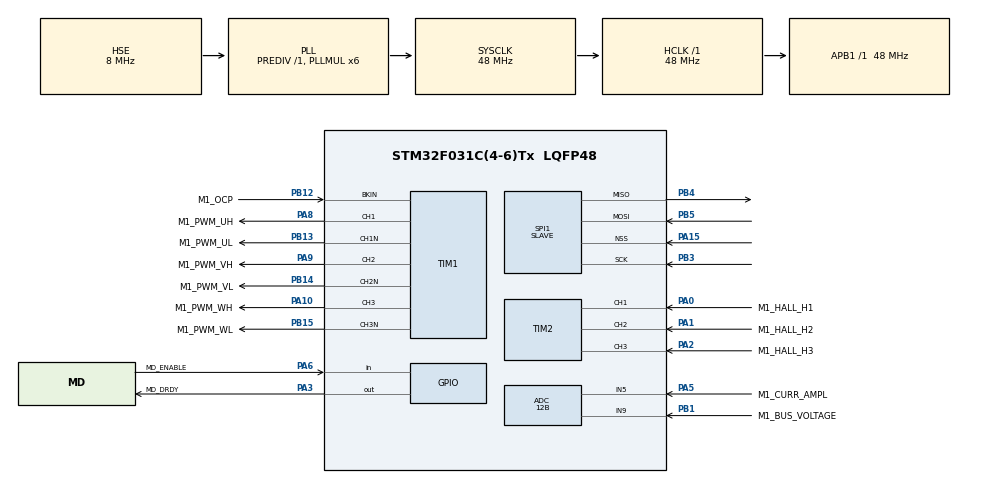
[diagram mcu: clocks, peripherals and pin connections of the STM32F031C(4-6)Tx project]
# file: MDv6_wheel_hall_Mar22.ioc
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ADC.ClockPrescaler=ADC_CLOCK_ASYNC_DIV1
ADC.ContinuousConvMode=DISABLE
ADC.DMAContinuousRequests=ENABLE
ADC.DataAlign=ADC_DATAALIGN_LEFT
ADC.DiscontinuousConvMode=DISABLE
ADC.EOCSelection=ADC_EOC_SINGLE_CONV
ADC.EnableAnalogWatchDog=false
ADC.ExternalTrigConv=ADC_EXTERNALTRIGCONV_T1_TRGO
ADC.ExternalTrigConvEdge=ADC_EXTERNALTRIGCONVEDGE_RISING
ADC.LowPowerAutoPowerOff=DISABLE
ADC.LowPowerAutoWait=DISABLE
ADC.Overrun=ADC_OVR_DATA_PRESERVED
ADC.Resolution=ADC_RESOLUTION_12B
ADC.SamplingTime=ADC_SAMPLETIME_7CYCLES_5
ADC.ScanConvMode=ADC_SCAN_DIRECTION_FORWARD
Dma.ADC.0.Direction=DMA_PERIPH_TO_MEMORY
Dma.ADC.0.Instance=DMA1_Channel1
Dma.ADC.0.MemDataAlignment=DMA_MDATAALIGN_HALFWORD
Dma.ADC.0.MemInc=DMA_MINC_ENABLE
Dma.ADC.0.Mode=DMA_CIRCULAR
Dma.ADC.0.PeriphDataAlignment=DMA_PDATAALIGN_HALFWORD
Dma.ADC.0.PeriphInc=DMA_PINC_DISABLE
Dma.ADC.0.Priority=DMA_PRIORITY_LOW
Dma.Request0=ADC
Dma.Request1=TIM1_CH4/TRIG/COM
Dma.Request2=TIM1_CH3/UP
Dma.Request3=SPI1_RX
Dma.Request4=SPI1_TX
Dma.SPI1_RX.3.Direction=DMA_PERIPH_TO_MEMORY
Dma.SPI1_RX.3.Instance=DMA1_Channel2
Dma.SPI1_RX.3.MemDataAlignment=DMA_MDATAALIGN_BYTE
Dma.SPI1_RX.3.MemInc=DMA_MINC_ENABLE
Dma.SPI1_RX.3.Mode=DMA_CIRCULAR
Dma.SPI1_RX.3.PeriphDataAlignment=DMA_PDATAALIGN_BYTE
Dma.SPI1_RX.3.PeriphInc=DMA_PINC_DISABLE
Dma.SPI1_RX.3.Priority=DMA_PRIORITY_LOW
Dma.SPI1_TX.4.Direction=DMA_MEMORY_TO_PERIPH
Dma.SPI1_TX.4.Instance=DMA1_Channel3
Dma.SPI1_TX.4.MemDataAlignment=DMA_MDATAALIGN_BYTE
Dma.SPI1_TX.4.MemInc=DMA_MINC_ENABLE
Dma.SPI1_TX.4.Mode=DMA_CIRCULAR
Dma.SPI1_TX.4.PeriphDataAlignment=DMA_PDATAALIGN_BYTE
Dma.SPI1_TX.4.PeriphInc=DMA_PINC_DISABLE
Dma.SPI1_TX.4.Priority=DMA_PRIORITY_LOW
Dma.TIM1_CH3/UP.2.Direction=DMA_MEMORY_TO_PERIPH
Dma.TIM1_CH3/UP.2.Instance=DMA1_Channel5
Dma.TIM1_CH3/UP.2.MemDataAlignment=DMA_MDATAALIGN_HALFWORD
Dma.TIM1_CH3/UP.2.MemInc=DMA_MINC_ENABLE
Dma.TIM1_CH3/UP.2.Mode=DMA_CIRCULAR
Dma.TIM1_CH3/UP.2.PeriphDataAlignment=DMA_PDATAALIGN_HALFWORD
Dma.TIM1_CH3/UP.2.PeriphInc=DMA_PINC_DISABLE
Dma.TIM1_CH3/UP.2.Priority=DMA_PRIORITY_HIGH
Dma.TIM1_CH4/TRIG/COM.1.Direction=DMA_MEMORY_TO_PERIPH
Dma.TIM1_CH4/TRIG/COM.1.Instance=DMA1_Channel4
Dma.TIM1_CH4/TRIG/COM.1.MemDataAlignment=DMA_MDATAALIGN_HALFWORD
Dma.TIM1_CH4/TRIG/COM.1.MemInc=DMA_MINC_ENABLE
Dma.TIM1_CH4/TRIG/COM.1.Mode=DMA_CIRCULAR
Dma.TIM1_CH4/TRIG/COM.1.PeriphDataAlignment=DMA_PDATAALIGN_HALFWORD
Dma.TIM1_CH4/TRIG/COM.1.PeriphInc=DMA_PINC_DISABLE
Dma.TIM1_CH4/TRIG/COM.1.Priority=DMA_PRIORITY_HIGH
ExtraMW=MotorControl
ExtraMW.MotorControl.Config=MotorControl
ExtraMW.MotorControl.Mode=MotorControl
ExtraMW.MotorControl.Root=MCSDK_v6.4.1-Full/MotorControl
ExtraMW.MotorControl.Template=templates
Mcu.Family=STM32F0
Mcu.Name=STM32F031C(4-6)Tx
Mcu.Package=LQFP48
MotorControl.ADC_AHBPERIPH=RCC_AHBPeriph_ADC
MotorControl.ADC_CLOCK_WB_DIV=1
MotorControl.ADC_PERIPH=ADC1
MotorControl.ADC_REFERENCE_VOLTAGE=3.3
MotorControl.BOARD=EVSPIN32F0251S1
MotorControl.BUS_VOLTAGE_READING=true
MotorControl.CCMRAM_ENABLED=false
MotorControl.CLOCK_FREQUENCY=CPU_CLK_48_MHZ
MotorControl.CLOCK_SOURCE=EXTERNAL
MotorControl.CONFIG_OC_SEL=false
MotorControl.CPU_CLK_48_MHZ=true
MotorControl.CTLBOARD_NAME=EVSPIN32F0251S1
MotorControl.CUBE_MX_VER=6.9.2
MotorControl.CURRENT_READING_TOPOLOGY=SINGLE_SHUNT
MotorControl.CURR_SAMPLING_TIME=7
MotorControl.DBG_MCU_LOAD_MEASURE=false
MotorControl.DEBUG_DAC_FUNCTIONALITY_EN=false
MotorControl.DRIVES_NUMBER_SELECTION=SINGLEDRIVE
MotorControl.DRIVE_NUMBER=1
MotorControl.DRIVE_TYPE=FOC
MotorControl.EMERGENCY_STOP_GPIO_PIN=LL_GPIO_PIN_12
MotorControl.EMERGENCY_STOP_GPIO_PORT=GPIOB
MotorControl.ENCODER_AVAILABLE=false
MotorControl.ENCODER_PPR=400
MotorControl.EN_DRIVER_AVAILABLE=true
MotorControl.EN_DRIVER_GPIO_PIN=LL_GPIO_PIN_11
MotorControl.EN_DRIVER_GPIO_PORT=GPIOA
MotorControl.EN_DRIVER_POLARITY=ACTIVE_LOW
MotorControl.EXT_CLK_8_MHZ=true
MotorControl.EXT_CLOCK_FREQUENCY=EXT_CLK_8_MHZ
MotorControl.FEEDBACK_NET_FILTERING=false
MotorControl.H1_GPIO_PIN=LL_GPIO_PIN_0
MotorControl.H1_GPIO_PORT=GPIOA
MotorControl.H2_GPIO_PIN=LL_GPIO_PIN_1
MotorControl.H2_GPIO_PORT=GPIOA
MotorControl.H3_GPIO_PIN=LL_GPIO_PIN_2
MotorControl.H3_GPIO_PORT=GPIOA
MotorControl.HALL_ICx_FILTER=34
MotorControl.HALL_SENSORS=true
MotorControl.HALL_SENSORS_AVAILABLE=true
MotorControl.HALL_TIMER_SELECTION=HALL_TIM2
MotorControl.HIGH_SIDE_IDLE_STATE=false
MotorControl.HWV_CS=SingleShunt_AmplifiedCurrents
MotorControl.HWV_OCP=SingleInput_RawCurrents_Protection_IntRef
MotorControl.HWV_PWM=PoweringHighAndLowSides
MotorControl.HW_COMPLEMENTED_LOW_SIDE=false
MotorControl.HW_DEAD_TIME_NS=700
MotorControl.IPs=NVIC,RCC,SYS,MotorControl,TIM1,ADC,TIM2,USART1,DMA
MotorControl.LOW_MEMORY_FOOTPRINT_REG=true
MotorControl.LOW_SIDE_IDLE_STATE=false
MotorControl.LOW_SIDE_SIGNALS_ENABLING=LS_PWM_TIMER
MotorControl.M1_AMPLIFICATION_GAIN=3.33
MotorControl.M1_ANGC={0,0,0,0,0,0,0,0}
MotorControl.M1_AUXILIARY_SPEED_SENSOR=NONE
MotorControl.M1_BOARD_MAX_CURRENT=9.5
MotorControl.M1_BUS_VOLTAGE_READING=true
MotorControl.M1_CONSTANT1_D=21860
MotorControl.M1_CONSTANT1_Q=21860
MotorControl.M1_CONSTANT2_QD=1876
MotorControl.M1_CS_ADC_NUM=1
MotorControl.M1_CS_ADC_PHASE_SHARED=NONE
MotorControl.M1_CS_ADC_U=ADC1
MotorControl.M1_CS_CHANNEL_U=5
MotorControl.M1_CURRENT_AMPLIFICATION_TOPO=EXTERNAL
MotorControl.M1_CURRENT_SENSING_TOPO=SINGLE_SHUNT_PHASE_SHIFT
MotorControl.M1_CURR_SAMPLING_TIME=7
MotorControl.M1_DBG_OPEN_LOOP_ENABLE=false
MotorControl.M1_DC_CURRENT_RS_MEAS=9.5
MotorControl.M1_DEFAULT_CONTROL_MODE=STC_SPEED_MODE
MotorControl.M1_DEFAULT_FLUX_COMPONENT=0
MotorControl.M1_DEFAULT_TARGET_SPEED_RPM=1742
MotorControl.M1_DEFAULT_TORQUE_COMPONENT=0
MotorControl.M1_DISCONTINUOUS_PWM=false
MotorControl.M1_DP_TOPOLOGY=NONE
MotorControl.M1_DRIVE_TYPE=FOC
MotorControl.M1_ENCODER_PPR=400
MotorControl.M1_FEED_FORWARD_CURRENT_REG_ENABLING=false
MotorControl.M1_FLUX_WEAKENING_ENABLING=false
MotorControl.M1_FW_KIDIV=32768
MotorControl.M1_FW_KI_GAIN=5000
MotorControl.M1_FW_KPDIV=32768
MotorControl.M1_FW_KP_GAIN=3000
MotorControl.M1_FW_VOLTAGE_REF=985
MotorControl.M1_HALL_AVERAGING_FIFO_DEPTH=16
MotorControl.M1_HALL_ICx_FILTER=34
MotorControl.M1_HALL_MTPA=false
MotorControl.M1_HALL_PHASE_SHIFT=270
MotorControl.M1_HALL_SENSORS_PLACEMENT=DEGREES_120
MotorControl.M1_HALL_TIMER_SELECTION=HALL_TIM2
MotorControl.M1_HIGH_SIDE_IDLE_STATE=false
MotorControl.M1_HW_DEAD_TIME_NS=700
MotorControl.M1_ICL_ENABLED=false
MotorControl.M1_ID_DEMAG=-9.5
MotorControl.M1_IQMAX=9.5
MotorControl.M1_LDLQ_RATIO=1.000
MotorControl.M1_LOW_SIDE_IDLE_STATE=false
MotorControl.M1_LOW_SIDE_SIGNALS_ENABLING=LS_PWM_TIMER
MotorControl.M1_LS=0.00027
MotorControl.M1_MAX_APPLICATION_SPEED=4840
MotorControl.M1_MAX_MODULATION_INDEX=100
MotorControl.M1_MIN_APPLICATION_SPEED=0
MotorControl.M1_MOTOR_MAX_SPEED_RPM=4840
MotorControl.M1_MOTOR_NAME=DF45L024048-A2
MotorControl.M1_MOTOR_RATED_FLUX=0.023086441
MotorControl.M1_MOTOR_VOLTAGE_CONSTANT=3.8
MotorControl.M1_MTPA_ENABLING=false
MotorControl.M1_NOMINAL_BUS_VOLTAGE_V=24
MotorControl.M1_NOMINAL_CURRENT=9.5
MotorControl.M1_OCP_BKIN_FILTER=3
MotorControl.M1_OCP_BKIN_MODE=EXT_MODE
MotorControl.M1_OCP_BKIN_POLARITY=EMSTOP_ACTIVE_LOW
MotorControl.M1_OCP_DESTINATION=TIM_BKIN
MotorControl.M1_OCP_TOPOLOGY=EXTERNAL
MotorControl.M1_OFST={0,0,0,0,0,0,0,0}
MotorControl.M1_ON_OVER_VOLTAGE=TURN_OFF_PWM
MotorControl.M1_OVERMODULATION=false
MotorControl.M1_OVP_THRESHOLD_HIGH=29
MotorControl.M1_OV_VOLTAGE_PROT_ENABLING=true
MotorControl.M1_OV_VOLTAGE_THRESHOLD_V=29
MotorControl.M1_PID_FLUX_KD_DEFAULT=100
MotorControl.M1_PID_FLUX_KI_DEFAULT=3997
MotorControl.M1_PID_FLUX_KP_DEFAULT=2740
MotorControl.M1_PID_SPEED_KD_DEFAULT=0
MotorControl.M1_PID_SPEED_KI_DEFAULT=502
MotorControl.M1_PID_SPEED_KP_DEFAULT=2533
MotorControl.M1_PID_TORQUE_KD_DEFAULT=100
MotorControl.M1_PID_TORQUE_KI_DEFAULT=3997
MotorControl.M1_PID_TORQUE_KP_DEFAULT=2740
MotorControl.M1_POLE_PAIR_NUM=8
MotorControl.M1_POSITION_CTRL_ENABLING=false
MotorControl.M1_POTENTIOMETER_ENABLE=false
MotorControl.M1_POWERBOARD_NAME=EVSPIN32F0251S1
MotorControl.M1_PWM_CHARGE_BOOT_CAP_DUTY_CYCLES=0.000
MotorControl.M1_PWM_CHARGE_BOOT_CAP_MS=10
MotorControl.M1_PWM_DRIVER_PN=STSPIN32F0251_DRIVER
MotorControl.M1_PWM_FREQUENCY=13000
MotorControl.M1_PWM_TIMER_BRK_IRQ=TIM1_BRK_UP_TRG_COM
MotorControl.M1_PWM_TIMER_SELECTION=PWM_TIM1
MotorControl.M1_PWM_TIMER_UP_IRQ=TIM1_BRK_UP_TRG_COM
MotorControl.M1_REGULATION_EXECUTION_RATE=2
MotorControl.M1_RS=0.64
MotorControl.M1_RSHUNT=0.025
MotorControl.M1_SEGDIV=0
MotorControl.M1_SHARED_SIGNAL_ENABLE=false
MotorControl.M1_SPD_DIFFERENTIAL_TERM_ENABLING=false
MotorControl.M1_SPEED_LOOP_FREQUENCY_HZ=1000
MotorControl.M1_SPEED_SENSOR=HALL_SENSOR
MotorControl.M1_SP_KDDIV=16
MotorControl.M1_SP_KIDIV=16384
MotorControl.M1_SP_KPDIV=64
MotorControl.M1_SS_MEAS_ERRORS_BEFORE_FAULTS=3
MotorControl.M1_SW_DEADTIME_NS=600
MotorControl.M1_TEMPERATURE_READING=false
MotorControl.M1_TF_KDDIV=8192
MotorControl.M1_TF_KIDIV=4096
MotorControl.M1_TF_KPDIV=1024
MotorControl.M1_TNOISE_NS=1200
MotorControl.M1_TRISE_NS=1200
MotorControl.M1_UD_VOLTAGE_THRESHOLD_V=20
MotorControl.M1_USE_INTERNAL_OPAMP=false
MotorControl.M1_UV_VOLTAGE_PROT_ENABLING=true
MotorControl.M1_VBUS_ADC=ADC1
MotorControl.M1_VBUS_ADC_SAMPLING_TIME=13
MotorControl.M1_VBUS_CHANNEL=ADC_CHANNEL_9
MotorControl.M1_VBUS_PARTITIONING_FACTOR=0.020145044319097503
MotorControl.MAX_READABLE_CURRENT=19.821
MotorControl.MCP_ASPEP_OVER_UART=true
MotorControl.MCP_ASYNC_EN=false
MotorControl.MCP_ASYNC_OVER_ASPEP_EN=false
MotorControl.MCP_ASYNC_OVER_UART_A_EN=false
MotorControl.MCP_DMACH_RX_UART_A=3
MotorControl.MCP_DMACH_TX_UART_A=2
MotorControl.MCP_DMA_RX_UART_A=DMA1
MotorControl.MCP_DMA_TX_UART_A=DMA1
MotorControl.MCP_EN=true
MotorControl.MCP_IRQ_HANDLER_DMA_RX_UART_A=DMA1_Channel2_3_IRQHandler
MotorControl.MCP_IRQ_HANDLER_UART_A=USART1_IRQHandler
MotorControl.MCP_OVER_ASPEP_EN=true
MotorControl.MCP_OVER_STLNK_EN=false
MotorControl.MCP_OVER_UART_A_EN=true
MotorControl.MCP_OVER_UART_B_EN=false
MotorControl.MCP_RX_SYNC_PAYLOAD_MAX=128
MotorControl.MCP_TX_SYNC_PAYLOAD_MAX=128
MotorControl.MCU=STSPIN32F0251
MotorControl.MCU_FAMILY=STM32F0
MotorControl.MCU_LINE=STM32F0x1
MotorControl.MCU_NAME=STM32F031C(4-6)Tx
MotorControl.MCU_PACKAGE=LQFP48
MotorControl.MCU_TYPE=STSPIN32F0251
MotorControl.MCU_USERNAME=STM32F031C6Tx
MotorControl.MC_WORKBENCH_VERSION=6.2.0
MotorControl.MOTOR_PROFILER=false
MotorControl.MOTOR_TYPE=PMSM
MotorControl.OCP_INT_REF=460
MotorControl.OCTH_STBY_GPIO=false
MotorControl.ON_OVER_VOLTAGE=TURN_OFF_PWM
MotorControl.OV_VOLTAGE_PROT_ENABLING=true
MotorControl.PHASE_CURRENTS_ADC=ADC1
MotorControl.PHASE_CURRENTS_CHANNEL=ADC_CHANNEL_5
MotorControl.PHASE_CURRENTS_GPIO_PIN=LL_GPIO_PIN_5
MotorControl.PHASE_CURRENTS_GPIO_PORT=GPIOA
MotorControl.PHASE_UH_GPIO_PIN=LL_GPIO_PIN_8
MotorControl.PHASE_UH_GPIO_PORT=GPIOA
MotorControl.PHASE_UH_POLARITY=H_ACTIVE_LOW
MotorControl.PHASE_UL_GPIO_PIN=LL_GPIO_PIN_13
MotorControl.PHASE_UL_GPIO_PORT=GPIOB
MotorControl.PHASE_UL_POLARITY=L_ACTIVE_LOW
MotorControl.PHASE_VH_GPIO_PIN=LL_GPIO_PIN_9
MotorControl.PHASE_VH_GPIO_PORT=GPIOA
MotorControl.PHASE_VH_POLARITY=H_ACTIVE_LOW
MotorControl.PHASE_VL_GPIO_PIN=LL_GPIO_PIN_14
MotorControl.PHASE_VL_GPIO_PORT=GPIOB
MotorControl.PHASE_VL_POLARITY=L_ACTIVE_LOW
MotorControl.PHASE_WH_GPIO_PIN=LL_GPIO_PIN_10
MotorControl.PHASE_WH_GPIO_PORT=GPIOA
MotorControl.PHASE_WH_POLARITY=H_ACTIVE_LOW
MotorControl.PHASE_WL_GPIO_PIN=LL_GPIO_PIN_15
MotorControl.PHASE_WL_GPIO_PORT=GPIOB
MotorControl.PHASE_WL_POLARITY=L_ACTIVE_LOW
MotorControl.POTENTIOMETER_READING=false
MotorControl.PWM_FREQUENCY=13000
MotorControl.PWM_TIMER_SELECTION=PWM_TIM1
MotorControl.REGULATION_EXECUTION_RATE=2
MotorControl.RTOS=NONE
MotorControl.R_BRAKE_SWITCH_OFF_THRES_V=23
MotorControl.SINGLEDRIVE=true
MotorControl.SINGLE_SHUNT=true
MotorControl.SPD_DIFFERENTIAL_TERM_ENABLING=false
MotorControl.SPEED_SENSOR_SELECTION=HALL_SENSORS
MotorControl.START_STOP_BTN=true
MotorControl.START_STOP_GPIO_PIN=LL_GPIO_PIN_15
MotorControl.START_STOP_GPIO_PORT=GPIOC
MotorControl.START_STOP_POLARITY=DIN_ACTIVE_LOW
MotorControl.START_STOP_POLARITY_EDGE=GPIO_PULLUP
MotorControl.STSPIN32F0251=true
MotorControl.SW_DEADTIME_NS=600
MotorControl.TEMPERATURE_READING=false
MotorControl.TFDIFFERENTIAL_TERM_ENABLING=false
MotorControl.TRISE_NS=1200
MotorControl.USART_RX_GPIO_PIN=LL_GPIO_PIN_7
MotorControl.USART_RX_GPIO_PORT=GPIOB
MotorControl.USART_SELECTION=USE_USART1
MotorControl.USART_SELECTION_A=USART1
MotorControl.USART_SPEED=1843200
MotorControl.USART_TX_GPIO_PIN=LL_GPIO_PIN_6
MotorControl.USART_TX_GPIO_PORT=GPIOB
MotorControl.USE_3OPAMPS=false
MotorControl.USE_INTERNAL_OPAMP=false
MotorControl.UV_VOLTAGE_PROT_ENABLING=true
MotorControl.VBUS_ADC=ADC1
MotorControl.VBUS_ADC_SAMPLING_TIME=13
MotorControl.VBUS_CHANNEL=ADC_CHANNEL_9
MotorControl.VBUS_GPIO_PIN=LL_GPIO_PIN_1
MotorControl.VBUS_GPIO_PORT=GPIOB
MotorControl.WB_UI_CUTOFF_FREQUENCY=6000
MotorControl.WB_UI_ENCODER_HAS_INDEX_PIN=false
MotorControl.WB_UI_FLUX_TARGET=0
MotorControl.WB_UI_FRICTION=14
MotorControl.WB_UI_INERTIA=18.1
MotorControl.WB_UI_MAGNETIC_STRUCTURE=SM-PMSM
MotorControl.WB_UI_MAX_CURRENT=9.5
MotorControl.WB_UI_MAX_NOMINAL_DC_VOLTAGE=24
MotorControl.WB_UI_MOTOR_DESCRIPTION=Motor low voltage 
MotorControl.WB_UI_OCP_OCCOMPARATOR_THRESHOLD=0.46
MotorControl.WB_UI_OCP_SINGLEINPUT_INDEPENDENT_WIRES={'CURRENT_INPUT_P'\:{'ip'\:'COMP0','pin'\:'CIN','peripheral'\:'COMP0_INP','help'\:'','cost'\:0}}
MotorControl.WB_UI_OCP_THRESHOLD=16.36
MotorControl.WB_UI_PW_BOARD_MAX_RATED_CURRENT=16.6
MotorControl.WB_UI_PW_BOARD_MAX_VOLTAGE=164
MotorControl.WB_UI_PW_BOARD_MIN_VOLTAGE=20
MotorControl.WB_UI_VPOL=1.65
MotorControl.WB_to_Mx_template_version=23-09-08
MotorControl.WB_to_Mx_version=6.2.0
NVIC.DMA1_Channel1_IRQn=true\:1\:0\:true\:true\:false\:2\:true\:true\:true
NVIC.DMA1_Channel2_3_IRQn=true\:0\:0\:false\:false\:true\:true\:true\:true
NVIC.DMA1_Channel4_5_IRQn=true\:0\:0\:true\:true\:false\:3\:true\:true\:true
NVIC.TIM1_BRK_UP_TRG_COM_IRQn=true\:0\:0\:false\:true\:false\:5\:true\:true\:true
NVIC.TIM2_IRQn=true\:3\:0\:false\:true\:false\:6\:true\:true\:true
PA0.GPIO_Label=M1_HALL_H1
PA0.GPIO_Speed=GPIO_SPEED_FREQ_HIGH
PA0.Signal=S_TIM2_CH1_ETR
PA1.GPIO_Label=M1_HALL_H2
PA1.GPIO_Speed=GPIO_SPEED_FREQ_HIGH
PA1.Signal=S_TIM2_CH2
PA10.GPIO_Label=M1_PWM_WH
PA10.GPIO_PuPd=GPIO_PULLUP
PA10.GPIO_Speed=GPIO_SPEED_FREQ_HIGH
PA10.Signal=S_TIM1_CH3
PA13.GPIO_Label=TMS
PA13.Mode=Serial_Wire
PA13.Signal=SYS_SWDIO
PA14.GPIO_Label=TCK
PA14.Mode=Serial_Wire
PA14.Signal=SYS_SWCLK
PA15.Mode=NSS_Signal_Hard_Input
PA15.Signal=SPI1_NSS
PA2.GPIO_Label=M1_HALL_H3
PA2.GPIO_Speed=GPIO_SPEED_FREQ_HIGH
PA2.Signal=S_TIM2_CH3
PA3.GPIO_Label=MD_DRDY
PA3.GPIO_PuPd=GPIO_NOPULL
PA3.GPIO_Speed=GPIO_SPEED_FREQ_HIGH
PA3.Signal=GPIO_Output
PA5.GPIO_Label=M1_CURR_AMPL
PA5.Mode=IN5
PA5.Signal=ADC_IN5
PA6.GPIO_Label=MD_ENABLE
PA6.GPIO_Mode=GPIO_MODE_INPUT
PA6.GPIO_PuPd=GPIO_PULLUP
PA6.Signal=GPIO_Input
PA8.GPIO_Label=M1_PWM_UH
PA8.GPIO_PuPd=GPIO_PULLUP
PA8.GPIO_Speed=GPIO_SPEED_FREQ_HIGH
PA8.Signal=S_TIM1_CH1
PA9.GPIO_Label=M1_PWM_VH
PA9.GPIO_PuPd=GPIO_PULLUP
PA9.GPIO_Speed=GPIO_SPEED_FREQ_HIGH
PA9.Signal=S_TIM1_CH2
PB1.GPIO_Label=M1_BUS_VOLTAGE
PB1.Mode=IN9
PB1.Signal=ADC_IN9
PB12.GPIO_Label=M1_OCP
PB12.GPIO_PuPd=GPIO_PULLUP
PB12.Mode=Activate-Break-Input
PB12.Signal=TIM1_BKIN
PB13.GPIO_Label=M1_PWM_UL
PB13.GPIO_PuPd=GPIO_PULLUP
PB13.GPIO_Speed=GPIO_SPEED_FREQ_HIGH
PB13.Mode=PWM Generation1 CH1 CH1N
PB13.Signal=TIM1_CH1N
PB14.GPIO_Label=M1_PWM_VL
PB14.GPIO_PuPd=GPIO_PULLUP
PB14.GPIO_Speed=GPIO_SPEED_FREQ_HIGH
PB14.Mode=PWM Generation2 CH2 CH2N
PB14.Signal=TIM1_CH2N
PB15.GPIO_Label=M1_PWM_WL
PB15.GPIO_PuPd=GPIO_PULLUP
PB15.GPIO_Speed=GPIO_SPEED_FREQ_HIGH
PB15.Mode=PWM Generation3 CH3 CH3N
PB15.Signal=TIM1_CH3N
PB3.Mode=Full_Duplex_Slave
PB3.Signal=SPI1_SCK
PB4.Mode=Full_Duplex_Slave
PB4.Signal=SPI1_MISO
PB5.Mode=Full_Duplex_Slave
PB5.Signal=SPI1_MOSI
PB6.GPIO_Label=UART_TX
PB6.GPIO_Mode=GPIO_MODE_AF_PP
PB6.GPIO_PuPd=GPIO_NOPULL
PB6.GPIO_Speed=GPIO_SPEED_FREQ_LOW
PB6.Signal=USART1_TX
PB7.GPIO_Label=UART_RX
PB7.GPIO_Mode=GPIO_MODE_AF_PP
PB7.GPIO_PuPd=GPIO_NOPULL
PB7.GPIO_Speed=GPIO_SPEED_FREQ_LOW
PB7.Signal=USART1_RX
PF0-OSC_IN.Mode=HSE-External-Oscillator
PF0-OSC_IN.Signal=RCC_OSC_IN
PF1-OSC_OUT.Mode=HSE-External-Oscillator
PF1-OSC_OUT.Signal=RCC_OSC_OUT
ProjectManager.HeapSize=0x80
ProjectManager.StackSize=0x400
ProjectManager.TargetToolchain=STM32CubeIDE
RCC.AHBFreq_Value=48000000
RCC.APB1Freq_Value=48000000
RCC.APB1TimFreq_Value=48000000
RCC.EnbaleCSS=true
RCC.HCLKFreq_Value=48000000
RCC.HSE_VALUE=8000000
RCC.PLLMUL=RCC_PLL_MUL6
RCC.PLLSourceVirtual=RCC_PLLSOURCE_HSE
RCC.PREFETCH_ENABLE=1
RCC.SYSCLKFreq_VALUE=48000000
RCC.SYSCLKSource=RCC_SYSCLKSOURCE_PLLCLK
SH.S_TIM1_CH1.0=TIM1_CH1,PWM Generation1 CH1 CH1N
SH.S_TIM1_CH2.0=TIM1_CH2,PWM Generation2 CH2 CH2N
SH.S_TIM1_CH3.0=TIM1_CH3,PWM Generation3 CH3 CH3N
SH.S_TIM2_CH1_ETR.0=TIM2_CH1,Xored_Inputs_Hall_Sensor_Interface
SH.S_TIM2_CH2.0=TIM2_CH2,Xored_Inputs_Hall_Sensor_Interface
SH.S_TIM2_CH3.0=TIM2_CH3,Xored_Inputs_Hall_Sensor_Interface
SPI1.DataSize=SPI_DATASIZE_8BIT
SPI1.Direction=SPI_DIRECTION_2LINES
SPI1.Mode=SPI_MODE_SLAVE
SPI1.VirtualNSS=VM_NSSHARD
SPI1.VirtualType=VM_SLAVE
TIM1.AutoReloadPreload=TIM_AUTORELOAD_PRELOAD_DISABLE
TIM1.AutomaticOutput=TIM_AUTOMATICOUTPUT_DISABLE
TIM1.BreakPolarity=TIM_BREAKPOLARITY_LOW
TIM1.BreakState=TIM_BREAK_ENABLE
TIM1.Channel-PWM\ Generation1\ CH1\ CH1N=TIM_CHANNEL_1
TIM1.Channel-PWM\ Generation2\ CH2\ CH2N=TIM_CHANNEL_2
TIM1.Channel-PWM\ Generation3\ CH3\ CH3N=TIM_CHANNEL_3
TIM1.Channel-PWM\ Generation4\ No\ Output=TIM_CHANNEL_4
TIM1.ClockDivision=TIM_CLOCKDIVISION_DIV2
TIM1.CounterMode=TIM_COUNTERMODE_CENTERALIGNED2
TIM1.DeadTime=((DEAD_TIME_COUNTS) / 2)
TIM1.LockLevel=TIM_LOCKLEVEL_OFF
TIM1.OC1Preload_PWM=ENABLE
TIM1.OC2Preload_PWM=ENABLE
TIM1.OC3Preload_PWM=ENABLE
TIM1.OC4Preload_PWM=ENABLE
TIM1.OCIdleState_1=TIM_OCIDLESTATE_SET
TIM1.OCIdleState_2=TIM_OCIDLESTATE_SET
TIM1.OCIdleState_3=TIM_OCIDLESTATE_SET
TIM1.OCIdleState_4=TIM_OCIDLESTATE_RESET
TIM1.OCMode_PWM-PWM\ Generation1\ CH1\ CH1N=TIM_OCMODE_PWM1
TIM1.OCMode_PWM-PWM\ Generation2\ CH2\ CH2N=TIM_OCMODE_PWM1
TIM1.OCMode_PWM-PWM\ Generation3\ CH3\ CH3N=TIM_OCMODE_PWM1
TIM1.OCMode_PWM-PWM\ Generation4\ No\ Output=TIM_OCMODE_PWM2
TIM1.OCNIdleState_1=TIM_OCNIDLESTATE_SET
TIM1.OCNIdleState_2=TIM_OCNIDLESTATE_SET
TIM1.OCNIdleState_3=TIM_OCNIDLESTATE_SET
TIM1.OCNPolarity_1=TIM_OCNPOLARITY_LOW
TIM1.OCNPolarity_2=TIM_OCNPOLARITY_LOW
TIM1.OCNPolarity_3=TIM_OCNPOLARITY_LOW
TIM1.OCPolarity_1=TIM_OCPOLARITY_LOW
TIM1.OCPolarity_2=TIM_OCPOLARITY_LOW
TIM1.OCPolarity_3=TIM_OCPOLARITY_LOW
TIM1.OCPolarity_4=TIM_OCPOLARITY_HIGH
TIM1.OffStateIDLEMode=TIM_OSSI_ENABLE
TIM1.OffStateRunMode=TIM_OSSR_ENABLE
TIM1.Period=((PWM_PERIOD_CYCLES) / 2)
TIM1.Prescaler=((TIM_CLOCK_DIVIDER) - 1)
TIM1.Pulse-PWM\ Generation1\ CH1\ CH1N=((PWM_PERIOD_CYCLES) / 4)
TIM1.Pulse-PWM\ Generation2\ CH2\ CH2N=((PWM_PERIOD_CYCLES) / 4)
TIM1.Pulse-PWM\ Generation3\ CH3\ CH3N=((PWM_PERIOD_CYCLES) / 4)
TIM1.Pulse-PWM\ Generation4\ No\ Output=(((PWM_PERIOD_CYCLES) / 2) - (HTMIN))
TIM1.RepetitionCounter=(REP_COUNTER)
TIM1.TIM_MasterOutputTrigger=TIM_TRGO_UPDATE
TIM1.TIM_MasterSlaveMode=TIM_MASTERSLAVEMODE_DISABLE
TIM2.IC1Filter=M1_HALL_IC_FILTER
TIM2.Period=M1_HALL_TIM_PERIOD
VP_MotorControl_MC_ENABLED.Mode=Enabled
VP_TIM1_VS_no_output4.Mode=PWM Generation4 No Output
VP_TIM2_VS_ClockSourceINT.Mode=Internal
board=custom

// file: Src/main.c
/* USER CODE BEGIN Header */
/**
 ******************************************************************************
 * @file           : main.c
 * @brief          : Main program body
 ******************************************************************************
 * @attention
 *
 * Copyright (c) 2025 STMicroelectronics.
 * All rights reserved.
 *
 * This software is licensed under terms that can be found in the LICENSE file
 * in the root directory of this software component.
 * If no LICENSE file comes with this software, it is provided AS-IS.
 *
 ******************************************************************************
 */
/* USER CODE END Header */
#include "main.h"

/* USER CODE BEGIN Includes */
#include "crc.h"

#include <string.h>
/* USER CODE END Includes */

ADC_HandleTypeDef hadc;
DMA_HandleTypeDef hdma_adc;

TIM_HandleTypeDef htim1;
TIM_HandleTypeDef htim2;
DMA_HandleTypeDef hdma_tim1_ch4_trig_com;
DMA_HandleTypeDef hdma_tim1_ch3_up;

SPI_HandleTypeDef hspi1;
DMA_HandleTypeDef hdma_spi1_rx;
DMA_HandleTypeDef hdma_spi1_tx;

uint8_t rx_bufs[2][FRAME_SIZE];
uint8_t tx_bufs[2][FRAME_SIZE];

volatile bool txrx_half_completed;
volatile bool txrx_completed;

responseType_t response_type;

bool motor_enabled;

extern PID_Handle_t PIDSpeedHandle_M1;
extern PID_Handle_t PIDIqHandle_M1;
extern PID_Handle_t PIDIdHandle_M1;

void SystemClock_Config(void);
static void MX_GPIO_Init(void);
static void MX_DMA_Init(void);
static void MX_ADC_Init(void);
static void MX_TIM1_Init(void);
static void MX_TIM2_Init(void);
static void MX_SPI1_Init(void);
static void MX_NVIC_Init(void);

/* USER CODE BEGIN PFP */
void ProcessSpiTransaction(uint8_t *rx, uint8_t *tx);

void ProcessRx_SetTargetSpeed(uint8_t *rx);
void ProcessRx_SetTargetTorque(uint8_t *rx);
void ProcessRx_SetResponseType(uint8_t *rx);
void ProcessRx_SetPidTorqueKpKi(uint8_t *rx);
void ProcessRx_SetPidFluxKpKi(uint8_t *rx);
void ProcessRx_SetPidSpeedKpKi(uint8_t *rx);

void PopulateTx_ResponseSpeedAndFaults(uint8_t *tx);
void PopulateTx_ResponseIqAndId(uint8_t *tx);

void SetMotorEnabled(bool enabled);
/* USER CODE END PFP */

int main(void) {

	/* MCU Configuration--------------------------------------------------------*/

	/* Reset of all peripherals, Initializes the Flash interface and the Systick. */
	HAL_Init();

	/* Configure the system clock */
	SystemClock_Config();

	/* Initialize all configured peripherals */
	MX_GPIO_Init();
	MX_DMA_Init();
	MX_ADC_Init();
	MX_TIM1_Init();
	MX_TIM2_Init();
	MX_SPI1_Init();
	MX_MotorControl_Init();

	/* Initialize interrupts */
	MX_NVIC_Init();

	/* USER CODE BEGIN 2 */

	memset(rx_bufs, 0, sizeof(rx_bufs));
	memset(tx_bufs, 0, sizeof(tx_bufs));

	txrx_half_completed = false;
	txrx_completed = false;

	response_type = SPEED_AND_FAULTS;

	motor_enabled = false;

	ProcessSpiTransaction(rx_bufs[0], tx_bufs[0]);
	ProcessSpiTransaction(rx_bufs[1], tx_bufs[1]);

	if (HAL_SPI_TransmitReceive_DMA(&hspi1, (uint8_t *)tx_bufs, (uint8_t *)rx_bufs, FRAME_SIZE * 2) != HAL_OK) {
		Error_Handler();
	}

	while (1) {
		if (txrx_half_completed) {
			ProcessSpiTransaction(rx_bufs[0], tx_bufs[0]);
			txrx_half_completed = false;
		}
		if (txrx_completed) {
			ProcessSpiTransaction(rx_bufs[1], tx_bufs[1]);
			txrx_completed = false;
		}
	}

	/* USER CODE END 2 */
}

/**
 * Processes a complete SPI transaction by executing the received command
 * in the RX buffer and populating the TX buffer based on the current
 * response type.
 *
 * @param rx Pointer to the received SPI frame.
 * @param tx Pointer to the transmit SPI frame.
 */
void ProcessSpiTransaction(uint8_t *rx, uint8_t *tx) {
	uint8_t rx_copy[FRAME_SIZE];
	memcpy(rx_copy, rx, FRAME_SIZE);

	// Frame integrity check
	if (rx_copy[5] == CrcGenerateChecksum(rx_copy, FRAME_SIZE - 1)) {

		const opcode_t opcode = rx_copy[0];

		switch (opcode) {
			case NO_OP:
				break;
			case SET_TARGET_SPEED:
				ProcessRx_SetTargetSpeed(rx_copy);
				break;
			case SET_TARGET_TORQUE:
				ProcessRx_SetTargetTorque(rx_copy);
				break;
			case SET_RESPONSE_TYPE:
				ProcessRx_SetResponseType(rx_copy);
				break;
			case SET_PID_TORQUE_KP_KI:
				ProcessRx_SetPidTorqueKpKi(rx_copy);
				break;
			case SET_PID_FLUX_KP_KI:
				ProcessRx_SetPidFluxKpKi(rx_copy);
				break;
			case SET_PID_SPEED_KP_KI:
				ProcessRx_SetPidSpeedKpKi(rx_copy);
				break;
		}
	}

	switch (response_type) {
		case SPEED_AND_FAULTS:
			PopulateTx_ResponseSpeedAndFaults(tx);
			break;
		case IQ_AND_ID:
			PopulateTx_ResponseIqAndId(tx);
			break;
	}
}

/**
 * Processes the received SPI frame to update the target speed for
 * the motor and start/stop the motor based on the enable flag.
 *
 *  +--------+--------+---------------+-------+-------+
 *  | Opcode | Enable |     Speed     |       |  CRC  |
 *  +--------+--------+---------------+-------+-------+
 *      0        1        2       3       4       5
 */
void ProcessRx_SetTargetSpeed(uint8_t *rx) {
	const int16_t motor_target_speed = (rx[2] << 8) | rx[3];
	MC_ProgramSpeedRampMotor1(motor_target_speed, 0);
	SetMotorEnabled(rx[1]);
}

/**
 * Processes the received SPI frame to update the target torque for
 * the motor and start/stop the motor based on the enable flag.
 *
 *  +--------+--------+---------------+-------+-------+
 *  | Opcode | Enable |    Torque     |       |  CRC  |
 *  +--------+--------+---------------+-------+-------+
 *      0        1        2       3       4       5
 */
void ProcessRx_SetTargetTorque(uint8_t *rx) {
	const int16_t motor_target_torque = (rx[2] << 8) | rx[3];
	MC_ProgramTorqueRampMotor1(motor_target_torque, 0);
	SetMotorEnabled(rx[1]);
}

/**
 * Processes the received SPI frame to update the type of response
 * that will be sent back to the master in subsequent transactions.
 *
 *  +--------+--------+-----------------------+-------+
 *  | Opcode |  Type  |                       |  CRC  |
 *  +--------+--------+-----------------------+-------+
 *      0        1         2      3      4        5
 */
void ProcessRx_SetResponseType(uint8_t *rx) {
	response_type = rx[1];
}

/**
 * Processes the received SPI frame to update the Kp and Ki
 * parameters for the torque (Iq) PID controller.
 *
 *  +--------+----------------+---------------+-------+
 *  | Opcode |       Kp       |       Ki      |  CRC  |
 *  +--------+----------------+---------------+-------+
 *      0        1       2        3       4       5
 */
void ProcessRx_SetPidTorqueKpKi(uint8_t *rx) {
	const int16_t kp = (rx[1] << 8) | rx[2];
	const int16_t ki = (rx[3] << 8) | rx[4];

	PID_SetKP(&PIDIqHandle_M1, kp);
	PID_SetKI(&PIDIqHandle_M1, ki);
}

/**
 * Processes the received SPI frame to update the Kp and Ki
 * parameters for the flux (Id) PID controller.
 *
 *  +--------+----------------+---------------+-------+
 *  | Opcode |       Kp       |       Ki      |  CRC  |
 *  +--------+----------------+---------------+-------+
 *      0        1       2        3       4       5
 */
void ProcessRx_SetPidFluxKpKi(uint8_t *rx) {
	const int16_t kp = (rx[1] << 8) | rx[2];
	const int16_t ki = (rx[3] << 8) | rx[4];

	PID_SetKP(&PIDIdHandle_M1, kp);
	PID_SetKI(&PIDIdHandle_M1, ki);
}

/**
 * Processes the received SPI frame to update the Kp and Ki
 * parameters for the speed PID controller.
 *
 *  +--------+----------------+---------------+-------+
 *  | Opcode |       Kp       |       Ki      |  CRC  |
 *  +--------+----------------+---------------+-------+
 *      0        1       2        3       4       5
 */
void ProcessRx_SetPidSpeedKpKi(uint8_t *rx) {
	const int16_t kp = (rx[1] << 8) | rx[2];
	const int16_t ki = (rx[3] << 8) | rx[4];

	PID_SetKP(&PIDSpeedHandle_M1, kp);
	PID_SetKI(&PIDSpeedHandle_M1, ki);
}

/**
 * Populates the TX buffer with fields corresponding to the
 * current measured speed and motor faults.
 *
 *  +--------+---------------+----------------+-------+
 *  |  Type  |  Speed (RPM)  |     Faults     |  CRC  |
 *  +--------+---------------+----------------+-------+
 *      0        1       2        3      4       5
 */
void PopulateTx_ResponseSpeedAndFaults(uint8_t *tx) {
	const int16_t motor_current_speed = MC_GetMecSpeedAverageMotor1();
	const int16_t motor_faults = MC_GetOccurredFaultsMotor1();

	tx[0] = SPEED_AND_FAULTS;
	tx[1] = (motor_current_speed >> 8) & 0xFF;
	tx[2] = motor_current_speed & 0xFF;
	tx[3] = (motor_faults >> 8) & 0xFF;
	tx[4] = motor_faults & 0xFF;
	tx[5] = CrcGenerateChecksum(tx, FRAME_SIZE - 1);
}

/**
 * Populates the TX buffer with fields corresponding to the
 * current Iq and Id values for the motor.
 *
 *  +--------+---------------+----------------+-------+
 *  |  Type  |      Iq       |       Id       |  CRC  |
 *  +--------+---------------+----------------+-------+
 *      0        1       2        3      4       5
 */
void PopulateTx_ResponseIqAndId(uint8_t *tx) {
	const qd_t motor_iqd = MC_GetIqdMotor1();

	tx[0] = IQ_AND_ID;
	tx[1] = (motor_iqd.q >> 8) & 0xFF;
	tx[2] = motor_iqd.q & 0xFF;
	tx[3] = (motor_iqd.d >> 8) & 0xFF;
	tx[4] = motor_iqd.d & 0xFF;
	tx[5] = CrcGenerateChecksum(tx, FRAME_SIZE - 1);
}

/**
 * Enables or disables the motor based on the provided flag.
 *
 * @param enabled Whether to enable or disable the motor.
 */
void SetMotorEnabled(bool enabled) {
	if (enabled && !motor_enabled) {
		MC_StartMotor1();
	} else if (!enabled && motor_enabled) {
		MC_StopMotor1();
	}
	motor_enabled = enabled;
}

void SystemClock_Config(void) {
	RCC_OscInitTypeDef RCC_OscInitStruct = { 0 };
	RCC_ClkInitTypeDef RCC_ClkInitStruct = { 0 };

	/** Initializes the RCC Oscillators according to the specified parameters
	 * in the RCC_OscInitTypeDef structure.
	 */
	RCC_OscInitStruct.OscillatorType = RCC_OSCILLATORTYPE_HSI14
			| RCC_OSCILLATORTYPE_HSE;
	RCC_OscInitStruct.HSEState = RCC_HSE_ON;
	RCC_OscInitStruct.HSI14State = RCC_HSI14_ON;
	RCC_OscInitStruct.HSI14CalibrationValue = 16;
	RCC_OscInitStruct.PLL.PLLState = RCC_PLL_ON;
	RCC_OscInitStruct.PLL.PLLSource = RCC_PLLSOURCE_HSE;
	RCC_OscInitStruct.PLL.PLLMUL = RCC_PLL_MUL6;
	RCC_OscInitStruct.PLL.PREDIV = RCC_PREDIV_DIV1;
	if (HAL_RCC_OscConfig(&RCC_OscInitStruct) != HAL_OK) {
		Error_Handler();
	}

	/** Initializes the CPU, AHB and APB buses clocks
	 */
	RCC_ClkInitStruct.ClockType = RCC_CLOCKTYPE_HCLK | RCC_CLOCKTYPE_SYSCLK
			| RCC_CLOCKTYPE_PCLK1;
	RCC_ClkInitStruct.SYSCLKSource = RCC_SYSCLKSOURCE_PLLCLK;
	RCC_ClkInitStruct.AHBCLKDivider = RCC_SYSCLK_DIV1;
	RCC_ClkInitStruct.APB1CLKDivider = RCC_HCLK_DIV1;

	if (HAL_RCC_ClockConfig(&RCC_ClkInitStruct, FLASH_LATENCY_1) != HAL_OK) {
		Error_Handler();
	}

	/** Enables the Clock Security System
	 */
	HAL_RCC_EnableCSS();
}

/**
 * @brief NVIC Configuration.
 * @retval None
 */
static void MX_NVIC_Init(void) {
	/* DMA1_Channel1_IRQn interrupt configuration */
	HAL_NVIC_SetPriority(DMA1_Channel1_IRQn, 0, 0);
	HAL_NVIC_EnableIRQ(DMA1_Channel1_IRQn);
	/* DMA1_Channel4_5_IRQn interrupt configuration */
	HAL_NVIC_SetPriority(DMA1_Channel4_5_IRQn, 0, 0);
	HAL_NVIC_EnableIRQ(DMA1_Channel4_5_IRQn);
	/* DMA1_Channel2_3_IRQn interrupt configuration */
	HAL_NVIC_SetPriority(DMA1_Channel2_3_IRQn, 3, 0);
	HAL_NVIC_EnableIRQ(DMA1_Channel2_3_IRQn);
	/* TIM1_BRK_UP_TRG_COM_IRQn interrupt configuration */
	HAL_NVIC_SetPriority(TIM1_BRK_UP_TRG_COM_IRQn, 0, 0);
	HAL_NVIC_EnableIRQ(TIM1_BRK_UP_TRG_COM_IRQn);
	/* TIM2_IRQn interrupt configuration */
	HAL_NVIC_SetPriority(TIM2_IRQn, 2, 0);
	HAL_NVIC_EnableIRQ(TIM2_IRQn);
	/* EXTI4_15_IRQn interrupt configuration */
	HAL_NVIC_SetPriority(EXTI4_15_IRQn, 3, 0);
	HAL_NVIC_EnableIRQ(EXTI4_15_IRQn);
}

static void MX_ADC_Init(void) {

	ADC_ChannelConfTypeDef sConfig = { 0 };

	/** Configure the global features of the ADC (Clock, Resolution, Data Alignment and number of conversion)
	 */
	hadc.Instance = ADC1;
	hadc.Init.ClockPrescaler = ADC_CLOCK_ASYNC_DIV1;
	hadc.Init.Resolution = ADC_RESOLUTION_12B;
	hadc.Init.DataAlign = ADC_DATAALIGN_LEFT;
	hadc.Init.ScanConvMode = ADC_SCAN_DIRECTION_FORWARD;
	hadc.Init.EOCSelection = ADC_EOC_SINGLE_CONV;
	hadc.Init.LowPowerAutoWait = DISABLE;
	hadc.Init.LowPowerAutoPowerOff = DISABLE;
	hadc.Init.ContinuousConvMode = DISABLE;
	hadc.Init.DiscontinuousConvMode = DISABLE;
	hadc.Init.ExternalTrigConv = ADC_EXTERNALTRIGCONV_T1_TRGO;
	hadc.Init.ExternalTrigConvEdge = ADC_EXTERNALTRIGCONVEDGE_RISING;
	hadc.Init.DMAContinuousRequests = ENABLE;
	hadc.Init.Overrun = ADC_OVR_DATA_PRESERVED;
	if (HAL_ADC_Init(&hadc) != HAL_OK) {
		Error_Handler();
	}

	/** Configure for the selected ADC regular channel to be converted.
	 */
	sConfig.Channel = ADC_CHANNEL_5;
	sConfig.Rank = ADC_RANK_CHANNEL_NUMBER;
	sConfig.SamplingTime = ADC_SAMPLETIME_7CYCLES_5;
	if (HAL_ADC_ConfigChannel(&hadc, &sConfig) != HAL_OK) {
		Error_Handler();
	}

	/** Configure for the selected ADC regular channel to be converted.
	 */
	sConfig.Channel = ADC_CHANNEL_9;
	if (HAL_ADC_ConfigChannel(&hadc, &sConfig) != HAL_OK) {
		Error_Handler();
	}

}

static void MX_TIM1_Init(void) {

	TIM_MasterConfigTypeDef sMasterConfig = { 0 };
	TIM_OC_InitTypeDef sConfigOC = { 0 };
	TIM_BreakDeadTimeConfigTypeDef sBreakDeadTimeConfig = { 0 };

	htim1.Instance = TIM1;
	htim1.Init.Prescaler = ((TIM_CLOCK_DIVIDER) - 1);
	htim1.Init.CounterMode = TIM_COUNTERMODE_CENTERALIGNED2;
	htim1.Init.Period = ((PWM_PERIOD_CYCLES ) / 2);
	htim1.Init.ClockDivision = TIM_CLOCKDIVISION_DIV2;
	htim1.Init.RepetitionCounter = (REP_COUNTER );
	htim1.Init.AutoReloadPreload = TIM_AUTORELOAD_PRELOAD_DISABLE;
	if (HAL_TIM_PWM_Init(&htim1) != HAL_OK) {
		Error_Handler();
	}
	sMasterConfig.MasterOutputTrigger = TIM_TRGO_UPDATE;
	sMasterConfig.MasterSlaveMode = TIM_MASTERSLAVEMODE_DISABLE;
	if (HAL_TIMEx_MasterConfigSynchronization(&htim1, &sMasterConfig)
			!= HAL_OK) {
		Error_Handler();
	}
	sConfigOC.OCMode = TIM_OCMODE_PWM1;
	sConfigOC.Pulse = ((PWM_PERIOD_CYCLES ) / 4);
	sConfigOC.OCPolarity = TIM_OCPOLARITY_LOW;
	sConfigOC.OCNPolarity = TIM_OCNPOLARITY_LOW;
	sConfigOC.OCFastMode = TIM_OCFAST_DISABLE;
	sConfigOC.OCIdleState = TIM_OCIDLESTATE_SET;
	sConfigOC.OCNIdleState = TIM_OCNIDLESTATE_SET;
	if (HAL_TIM_PWM_ConfigChannel(&htim1, &sConfigOC, TIM_CHANNEL_1)
			!= HAL_OK) {
		Error_Handler();
	}
	if (HAL_TIM_PWM_ConfigChannel(&htim1, &sConfigOC, TIM_CHANNEL_2)
			!= HAL_OK) {
		Error_Handler();
	}
	if (HAL_TIM_PWM_ConfigChannel(&htim1, &sConfigOC, TIM_CHANNEL_3)
			!= HAL_OK) {
		Error_Handler();
	}
	sConfigOC.OCMode = TIM_OCMODE_PWM2;
	sConfigOC.Pulse = (((PWM_PERIOD_CYCLES ) / 2) - (HTMIN));
	sConfigOC.OCPolarity = TIM_OCPOLARITY_HIGH;
	sConfigOC.OCIdleState = TIM_OCIDLESTATE_RESET;
	sConfigOC.OCNIdleState = TIM_OCNIDLESTATE_RESET;
	if (HAL_TIM_PWM_ConfigChannel(&htim1, &sConfigOC, TIM_CHANNEL_4)
			!= HAL_OK) {
		Error_Handler();
	}
	sBreakDeadTimeConfig.OffStateRunMode = TIM_OSSR_ENABLE;
	sBreakDeadTimeConfig.OffStateIDLEMode = TIM_OSSI_ENABLE;
	sBreakDeadTimeConfig.LockLevel = TIM_LOCKLEVEL_OFF;
	sBreakDeadTimeConfig.DeadTime = ((DEAD_TIME_COUNTS ) / 2);
	sBreakDeadTimeConfig.BreakState = TIM_BREAK_ENABLE;
	sBreakDeadTimeConfig.BreakPolarity = TIM_BREAKPOLARITY_LOW;
	sBreakDeadTimeConfig.AutomaticOutput = TIM_AUTOMATICOUTPUT_DISABLE;
	if (HAL_TIMEx_ConfigBreakDeadTime(&htim1, &sBreakDeadTimeConfig)
			!= HAL_OK) {
		Error_Handler();
	}
	HAL_TIM_MspPostInit(&htim1);

}

static void MX_TIM2_Init(void) {

	TIM_ClockConfigTypeDef sClockSourceConfig = { 0 };
	TIM_HallSensor_InitTypeDef sConfig = { 0 };
	TIM_MasterConfigTypeDef sMasterConfig = { 0 };

	htim2.Instance = TIM2;
	htim2.Init.Prescaler = 0;
	htim2.Init.CounterMode = TIM_COUNTERMODE_UP;
	htim2.Init.Period = M1_HALL_TIM_PERIOD;
	htim2.Init.ClockDivision = TIM_CLOCKDIVISION_DIV1;
	htim2.Init.AutoReloadPreload = TIM_AUTORELOAD_PRELOAD_DISABLE;
	if (HAL_TIM_Base_Init(&htim2) != HAL_OK) {
		Error_Handler();
	}
	sClockSourceConfig.ClockSource = TIM_CLOCKSOURCE_INTERNAL;
	if (HAL_TIM_ConfigClockSource(&htim2, &sClockSourceConfig) != HAL_OK) {
		Error_Handler();
	}
	sConfig.IC1Polarity = TIM_ICPOLARITY_RISING;
	sConfig.IC1Prescaler = TIM_ICPSC_DIV1;
	sConfig.IC1Filter = M1_HALL_IC_FILTER;
	sConfig.Commutation_Delay = 0;
	if (HAL_TIMEx_HallSensor_Init(&htim2, &sConfig) != HAL_OK) {
		Error_Handler();
	}
	sMasterConfig.MasterOutputTrigger = TIM_TRGO_OC2REF;
	sMasterConfig.MasterSlaveMode = TIM_MASTERSLAVEMODE_DISABLE;
	if (HAL_TIMEx_MasterConfigSynchronization(&htim2, &sMasterConfig)
			!= HAL_OK) {
		Error_Handler();
	}

}

static void MX_DMA_Init(void) {

	/* DMA controller clock enable */
	__HAL_RCC_DMA1_CLK_ENABLE();

}

static void MX_GPIO_Init(void) {
	GPIO_InitTypeDef GPIO_InitStruct = { 0 };

	/* GPIO Ports Clock Enable */
	__HAL_RCC_GPIOF_CLK_ENABLE();
	__HAL_RCC_GPIOA_CLK_ENABLE();
	__HAL_RCC_GPIOB_CLK_ENABLE();

	/*Configure GPIO pin : M1_EN_DRIVER_Pin */
	GPIO_InitStruct.Pin = M1_EN_DRIVER_Pin;
	GPIO_InitStruct.Mode = GPIO_MODE_INPUT;
	GPIO_InitStruct.Pull = GPIO_PULLUP;
	GPIO_InitStruct.Speed = GPIO_SPEED_FREQ_LOW;
	HAL_GPIO_Init(M1_EN_DRIVER_GPIO_Port, &GPIO_InitStruct);

	/*Configure GPIO pin : M1_DRDY_Pin */
	GPIO_InitStruct.Pin = M1_DRDY_Pin;
	GPIO_InitStruct.Mode = GPIO_MODE_OUTPUT_PP;
	GPIO_InitStruct.Pull = GPIO_NOPULL;
	GPIO_InitStruct.Speed = GPIO_SPEED_FREQ_HIGH;
	HAL_GPIO_Init(M1_DRDY_GPIO_Port, &GPIO_InitStruct);

	/*Configure GPIO pin : M1_LED_Pin */
	GPIO_InitStruct.Pin = M1_LED_Pin;
	GPIO_InitStruct.Mode = GPIO_MODE_OUTPUT_PP;
	GPIO_InitStruct.Pull = GPIO_NOPULL;
	GPIO_InitStruct.Speed = GPIO_SPEED_FREQ_LOW;
	HAL_GPIO_Init(M1_LED_GPIO_Port, &GPIO_InitStruct);

}

static void MX_SPI1_Init(void) {
	hspi1.Instance = SPI1;
	hspi1.Init.Mode = SPI_MODE_SLAVE;
	hspi1.Init.Direction = SPI_DIRECTION_2LINES;
	hspi1.Init.DataSize = SPI_DATASIZE_8BIT;
	hspi1.Init.CLKPolarity = SPI_POLARITY_LOW;
	hspi1.Init.CLKPhase = SPI_PHASE_1EDGE;
	hspi1.Init.NSS = SPI_NSS_HARD_INPUT;
	hspi1.Init.FirstBit = SPI_FIRSTBIT_MSB;
	hspi1.Init.TIMode = SPI_TIMODE_DISABLE;
	hspi1.Init.CRCCalculation = SPI_CRCCALCULATION_DISABLE;
	hspi1.Init.CRCPolynomial = 7;
	hspi1.Init.CRCLength = SPI_CRC_LENGTH_DATASIZE;
	hspi1.Init.NSSPMode = SPI_NSS_PULSE_DISABLE;

	if (HAL_SPI_Init(&hspi1) != HAL_OK) {
		Error_Handler();
	}
}

/* USER CODE BEGIN 4 */

void HAL_SPI_TxRxHalfCpltCallback(SPI_HandleTypeDef* hspi) {
    if (hspi->Instance == SPI1) {
		txrx_half_completed = true;
	}
}

void HAL_SPI_TxRxCpltCallback(SPI_HandleTypeDef* hspi) {
    if (hspi->Instance == SPI1) {
		txrx_completed = true;
	}
}

void HAL_SPI_ErrorCallback(SPI_HandleTypeDef* hspi) {
    if (hspi->Instance == SPI1) {
    	// Do nothing for now
    }
}

/* USER CODE END 4 */

void Error_Handler(void) {
	__disable_irq();
	while (1) {
	}
}
